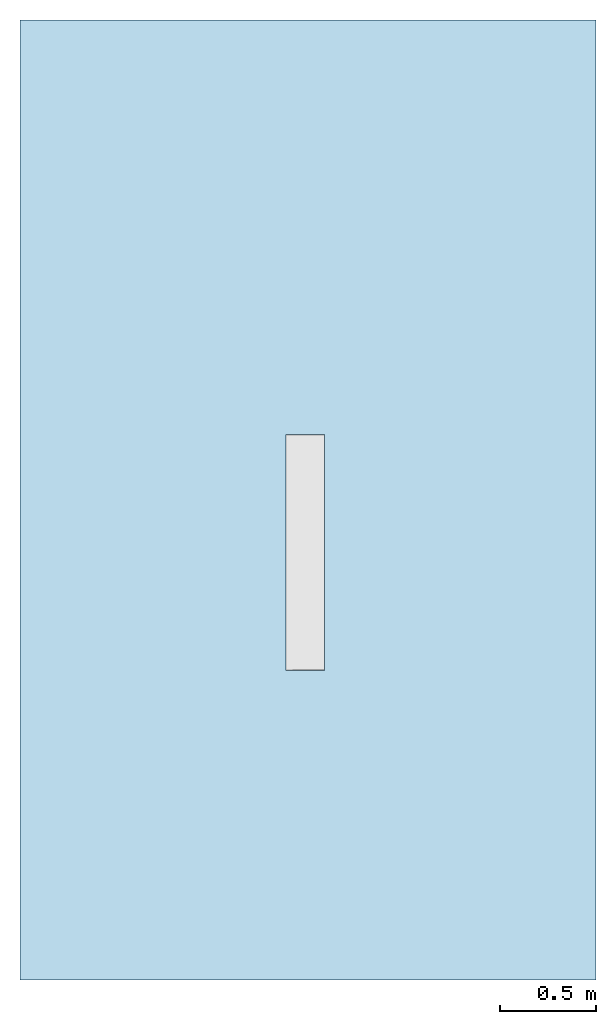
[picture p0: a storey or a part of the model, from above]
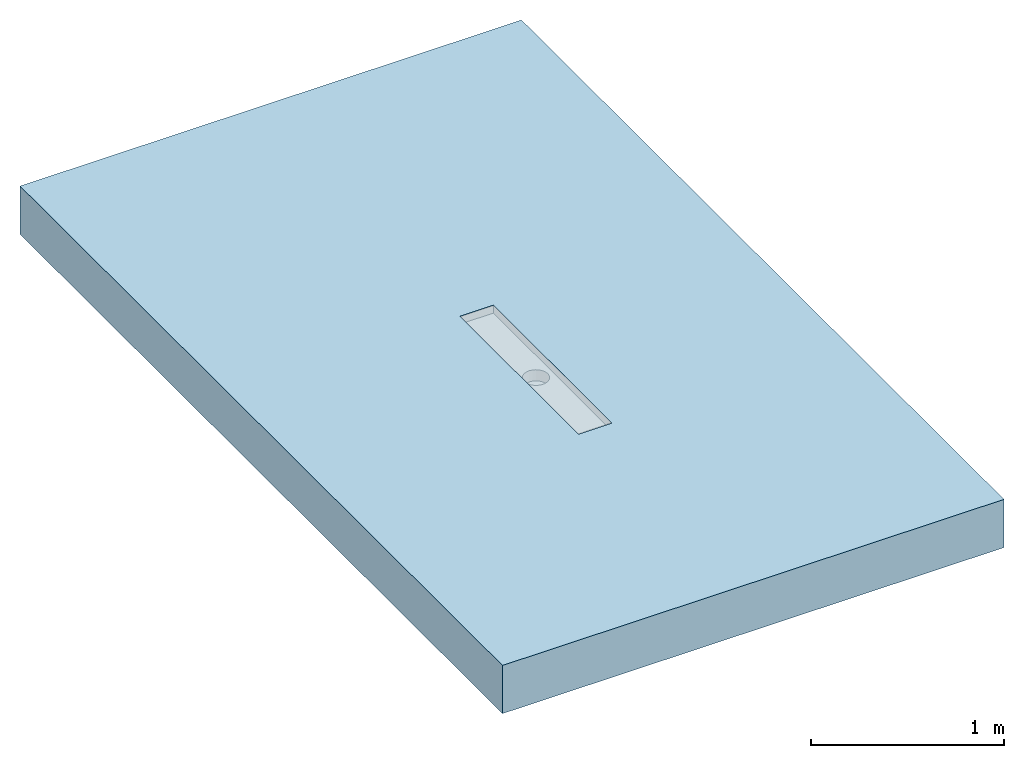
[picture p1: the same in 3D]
Properties of the parts of a building model (IFC2X3)

# File
Description: ViewDefinition [CoordinationView]
File name: Project Number
Time: 2016-11-22T10:21:56
Written by: The EXPRESS Data Manager Version 5.01.0100.02.64mod : 6 Jun 2012
Made in: 20130308_1515(x64) - Exporter 2014.0.2013.0308 - Default UI
Comment: STEP Physical File produced by: The EXPRESS Data Manager Version 5.01.0100.02.64mod : 6 Jun 2012 * Module: EDMstepFileFactory/EDMstandAlone * Creation date: Tue Nov 22 10:21:56 2016 * Host: IN-BLR-PC-0012 * Database: C:\Users\pakumar\AppData\Local\Temp\{D3AA29BE-847E-4401-B2C9-81866C30B5C8}\ifc * Database version: 5507 * Database creation date: Tue Nov 22 10:21:56 2016 * Schema: IFC2X3 * Model: DataRepository.ifc * Model creation date: Tue Nov 22 10:21:56 2016 * Header model: DataRepository.ifc_HeaderModel * Header model creation date: Tue Nov 22 10:21:56 2016 * EDMuser: sdai-user * EDMgroup: sdai-group * License ID and type: 5605 : Permanent license. Expiry date: * EDMstepFileFactory options: 020000

# IfcProject, Project Number
LongName: Project Name; Phase: Project Status

# IfcSite, Default
RefLatitude: 42, 21, 30, 344238; RefLongitude: -71, -3, -35, -194702; RefElevation: 0 mm

# IfcBuilding
Pset_BuildingCommon - NumberOfStoreys: 1
Other - Project Issue Date: Issue Date; Project Name: Project Name; Project Address: Enter address here; Client Name: Owner; Project Number: Project Number; Project Status: Project Status

# IfcBuildingStorey, Level 1
LongName: Level 1; Elevation: 0 mm
Constraints - Elevation Base: Project Base Point; Elevation: 0 mm
Graphics - Symbol at End 2 Default: yes; Symbol: Level Head - Circle: Level Head - Circle; Color: 0; Symbol at End 1 Default: no; Line Pattern: Grid Line 1/2"; Line Weight: 1
Identity Data - Building Story: yes; Name: Level 1; Structural: no
Dimensions - Computation Height: 0 mm

# IfcFlowTerminal: 416593 - Hygienic Standard Channel - with Gully 157 - 1200mm LG - 200mm Wide, ACO Tray Channel - Hygienic - Standard - 200mm Wide:416593 - Hygienic Standard Channel - with Gully 157 - 1200mm LG - 200mm Wide:489163
In: Level 1
Material: Stainless Steel AISI 304, Stainless Steel AISI 304 - Grating
Construction - Grating: yes; Detail - Outlet 142mm: yes; Detail - Outlet 125mm: no; Detail - Outlet 110mm: no; 416880 - 168 x 499mm - Mesh Grating - L15 - Stainless steel 1.4301: no; 416882 - 168 x 398mm - Mesh Grating - L15 - Stainless steel 1.4301: no; 416808 - 168 x 398mm - Ladder Grating - R50 - Stainless steel 1.4301: no; 416947 - 168 x 499mm - Casted Grating - M125 - Stainless steel 1.4301: yes; 416948 - 168 x 399mm - Casted Grating - M125 - Stainless steel 1.4301: no; 416804 - 168 x 499mm - Ladder Grating - M125 - Stainless steel 1.4301: no; 416860 - 168 x 499mm - Mesh Grating - L15 - Stainless steel 1.4301: no; 416810 - 168 x 398mm - Ladder Grating - M125 - Stainless steel 1.4301: no; 416862 - 168 x 398mm - Mesh Grating - L15 - Stainless steel 1.4301: no; 416802 - 168 x 499mm - Ladder Grating - R50 - Stainless steel 1.4301: no
Phasing - Phase Created: New Construction
Identity Data - Mark: 40; Telephone: +44 (0)1462 816666; Address: ACO Business Centre, Caxton Road, Bedford, MK41 0LF; Watermark2: This file is water marked and users are prohibited to reproduce, adapt, distribute this information; Manufacturer: ACO Building Drainage; Cost: 0; Watermark1: This file is the property of ACO Technologies PLC; E-mail Technical: abdtechnical@aco.co.uk; Website: www.acobd.com; Watermarked With: BIM Manager Premium Suite; Fax: +44 (0)1462 851490; E-mail Sales: abdcommercial@aco.co.uk; Watermarked By: www.acobd.com
Mechanical - System Classification: Sanitary
Constraints - Level: Level: Level 1
Pset_ManufacturerTypeInformation - Manufacturer: ACO Building Drainage
Dimensions - Spigot Distance: 600 mm; Outlet: 142 mm; Invert Depth: 50 mm; End Plate: 1200 mm; Grating Length: 399 mm; x: -1215 mm; Outside Outlet Rad: 71 mm; Endplate Position: 1200 mm; Floor Cut Void Height: 62.8 mm; Inside Outlet Rad: 69 mm; End Connection Plate End: -1200 mm; Grating Void Cut Length: 500 mm; Length Channel: -1170 mm; Number of gratings: 3; Grating Height: 21 mm; End Connection Plate Start: -1170 mm; Depth: 29 mm
Model Properties - Grating Product Code 416808: Load Class R 50 (EN 1253) - Ladder Grate - Stainless steel 1.4301 (EN 10088) - 168 x 398 - 2.3kg; Grating Product Code 416862: Load Class L 15 (EN 1253) - Mesh Grate - Stainless steel 1.4301 (EN 10088) - 168 x 398 - 1.7kg; Grating Product Code 416802: N/A; Grating Product Code 416804: N/A; Grating Product Code 416880: N/A; Grating Product Code 416882: Load Class L 15 (EN 1253) - Mesh Grate - Stainless steel 1.4301 (EN 10088) - 168 x 398 - 1.8kg; Grating Product Code 416860: N/A; Grating Product Code 416947: N/A; Grating Product Code 416810: Load Class M 125 (EN 1253) - Ladder Grate - Stainless steel 1.4301 (EN 10088) - 168 x 398 - 3.5kg; Grating Product Code 416948: Load Class M 125 (EN 1253) - Caste Grate - Stainless steel 1.4301 (EN 10088) - 168 x 399 - 5kg
Other - Length 1000: no; Array: 49; Invert Depth Detail: 51.5 mm; Length 500: no; Flow: 0.0988811 m3/s; Length 1500: no; Length 1200: yes; Spigot Outlets Channels: yes; Length 2000: no; Length 800: no
General - Load Class: A15 - C250 (EN 1253); Foul air trap Recycled material content: 0%; Product Range: ACO Hygiene First; Channel Recyclable: Fully recyclable; Installation guidelines: http://issuu.com/acobuildingdrainage/docs/aco_hygiene_first_catalogue/17?e=0; Channel Material: Stainless steel 1.4301 (EN 10088); Product Standard: EN 1253 / EN 1672 / EN ISO 14159; Product Code: 416593; Foul air trap Recyclable: Fully recyclable; Channel Colour: passivated stainless steel surface ( matt grey); Product Description: ACO Hygiene First Standard Kitchen Tray Channel 200 x 1230 / 142 Dia Outlet & Foul Air Trap; Maintenance guidelines: http://issuu.com/acobuildingdrainage/docs/aco_hygiene_first_catalogue/17?e=0; Price: POA - contact ACO; Foul air trap seal Material: NBR; Channel Recycled material content: 20 - 30 %; Weight (Kg): 5.4; Product Type: Standard Kitchen Tray Channel; Channel Dimension: 200 x 1230; Foul air trap seal Colour: Black; Outlet Diameter (mm): 142

# IfcOpeningElement: Recess
In: Level 1
Phasing - Phase Created: New Construction
Constraints - Level: Level: Level 1; Room Bounding: yes; Height Offset From Level: 0 mm; Related to Mass: no
Structural - Enable Analytical Model: no; Structural: no
Dimensions - Area: 161.459 ft2; Volume: 160.985 ft3; Perimeter: 16000 mm; Thickness: 304.8 mm
Identity Data - Assembly Code: B1010; Assembly Description: Floor Construction
Analytical Properties - Absorptance: 0.7; Roughness: 3
Construction - Default Thickness: 304.8 mm; Function: Interior
Graphics - Coarse Scale Fill Color: 0

# IfcSlab: Floor:Generic - 12", Floor:Generic - 12":184145
In: Level 1
PredefinedType: FLOOR; Material: Default Floor 304.8 mm
Phasing - Phase Created: New Construction
Constraints - Level: Level: Level 1; Room Bounding: yes; Height Offset From Level: 0 mm; Related to Mass: no
Structural - Enable Analytical Model: no; Structural: no
Dimensions - Area: 161.459 ft2; Volume: 160.985 ft3; Perimeter: 16000 mm; Thickness: 304.8 mm
Pset_SlabCommon - Reference: Generic - 12"; IsExternal: no; LoadBearing: yes
Identity Data - Assembly Code: B1010; Assembly Description: Floor Construction
Analytical Properties - Absorptance: 0.7; Roughness: 3
Construction - Default Thickness: 304.8 mm; Function: Interior
Graphics - Coarse Scale Fill Color: 0
